VERSION 5.7 ;
  NOWIREEXTENSIONATPIN ON ;
  DIVIDERCHAR "/" ;
  BUSBITCHARS "[]" ;
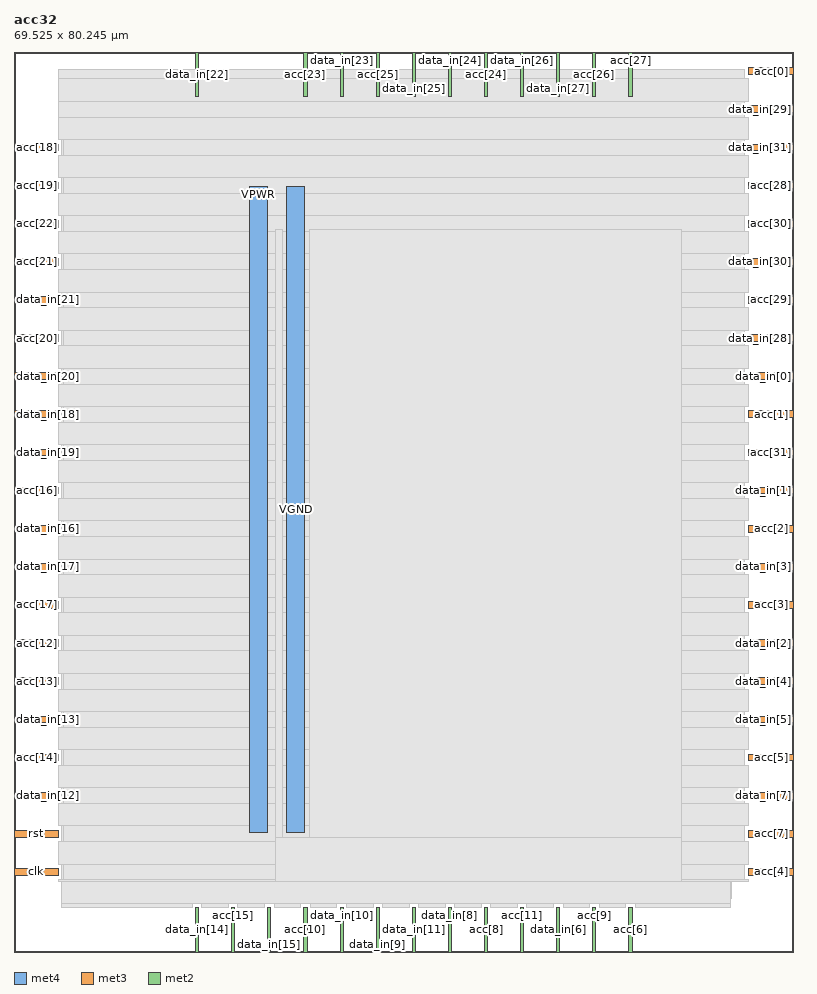
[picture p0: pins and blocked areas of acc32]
MACRO acc32
  CLASS BLOCK ;
  FOREIGN acc32 ;
  ORIGIN 0.000 0.000 ;
  SIZE 69.525 BY 80.245 ;
  PIN VGND
    DIRECTION INOUT ;
    USE GROUND ;
    PORT
      LAYER met4 ;
        RECT 24.340 10.640 25.940 68.240 ;
    END
  END VGND
  PIN VPWR
    DIRECTION INOUT ;
    USE POWER ;
    PORT
      LAYER met4 ;
        RECT 21.040 10.640 22.640 68.240 ;
    END
  END VPWR
  PIN acc[0]
    DIRECTION OUTPUT ;
    USE SIGNAL ;
    ANTENNADIFFAREA 0.445500 ;
    PORT
      LAYER met3 ;
        RECT 65.525 78.240 69.525 78.840 ;
    END
  END acc[0]
  PIN acc[10]
    DIRECTION OUTPUT ;
    USE SIGNAL ;
    ANTENNADIFFAREA 0.445500 ;
    PORT
      LAYER met2 ;
        RECT 25.850 0.000 26.130 4.000 ;
    END
  END acc[10]
  PIN acc[11]
    DIRECTION OUTPUT ;
    USE SIGNAL ;
    ANTENNADIFFAREA 0.445500 ;
    PORT
      LAYER met2 ;
        RECT 45.170 0.000 45.450 4.000 ;
    END
  END acc[11]
  PIN acc[12]
    DIRECTION OUTPUT ;
    USE SIGNAL ;
    ANTENNADIFFAREA 0.445500 ;
    PORT
      LAYER met3 ;
        RECT 0.000 27.240 4.000 27.840 ;
    END
  END acc[12]
  PIN acc[13]
    DIRECTION OUTPUT ;
    USE SIGNAL ;
    ANTENNADIFFAREA 0.445500 ;
    PORT
      LAYER met3 ;
        RECT 0.000 23.840 4.000 24.440 ;
    END
  END acc[13]
  PIN acc[14]
    DIRECTION OUTPUT ;
    USE SIGNAL ;
    ANTENNADIFFAREA 0.445500 ;
    PORT
      LAYER met3 ;
        RECT 0.000 17.040 4.000 17.640 ;
    END
  END acc[14]
  PIN acc[15]
    DIRECTION OUTPUT ;
    USE SIGNAL ;
    ANTENNADIFFAREA 0.445500 ;
    PORT
      LAYER met2 ;
        RECT 19.410 0.000 19.690 4.000 ;
    END
  END acc[15]
  PIN acc[16]
    DIRECTION OUTPUT ;
    USE SIGNAL ;
    ANTENNADIFFAREA 0.445500 ;
    PORT
      LAYER met3 ;
        RECT 0.000 40.840 4.000 41.440 ;
    END
  END acc[16]
  PIN acc[17]
    DIRECTION OUTPUT ;
    USE SIGNAL ;
    ANTENNADIFFAREA 0.445500 ;
    PORT
      LAYER met3 ;
        RECT 0.000 30.640 4.000 31.240 ;
    END
  END acc[17]
  PIN acc[18]
    DIRECTION OUTPUT ;
    USE SIGNAL ;
    ANTENNADIFFAREA 0.445500 ;
    PORT
      LAYER met3 ;
        RECT 0.000 71.440 4.000 72.040 ;
    END
  END acc[18]
  PIN acc[19]
    DIRECTION OUTPUT ;
    USE SIGNAL ;
    ANTENNADIFFAREA 0.445500 ;
    PORT
      LAYER met3 ;
        RECT 0.000 68.040 4.000 68.640 ;
    END
  END acc[19]
  PIN acc[1]
    DIRECTION OUTPUT ;
    USE SIGNAL ;
    ANTENNADIFFAREA 0.445500 ;
    PORT
      LAYER met3 ;
        RECT 65.525 47.640 69.525 48.240 ;
    END
  END acc[1]
  PIN acc[20]
    DIRECTION OUTPUT ;
    USE SIGNAL ;
    ANTENNADIFFAREA 0.445500 ;
    PORT
      LAYER met3 ;
        RECT 0.000 54.440 4.000 55.040 ;
    END
  END acc[20]
  PIN acc[21]
    DIRECTION OUTPUT ;
    USE SIGNAL ;
    ANTENNADIFFAREA 0.445500 ;
    PORT
      LAYER met3 ;
        RECT 0.000 61.240 4.000 61.840 ;
    END
  END acc[21]
  PIN acc[22]
    DIRECTION OUTPUT ;
    USE SIGNAL ;
    ANTENNADIFFAREA 0.445500 ;
    PORT
      LAYER met3 ;
        RECT 0.000 64.640 4.000 65.240 ;
    END
  END acc[22]
  PIN acc[23]
    DIRECTION OUTPUT ;
    USE SIGNAL ;
    ANTENNADIFFAREA 0.445500 ;
    PORT
      LAYER met2 ;
        RECT 25.850 76.245 26.130 80.245 ;
    END
  END acc[23]
  PIN acc[24]
    DIRECTION OUTPUT ;
    USE SIGNAL ;
    ANTENNADIFFAREA 0.445500 ;
    PORT
      LAYER met2 ;
        RECT 41.950 76.245 42.230 80.245 ;
    END
  END acc[24]
  PIN acc[25]
    DIRECTION OUTPUT ;
    USE SIGNAL ;
    ANTENNADIFFAREA 0.445500 ;
    PORT
      LAYER met2 ;
        RECT 32.290 76.245 32.570 80.245 ;
    END
  END acc[25]
  PIN acc[26]
    DIRECTION OUTPUT ;
    USE SIGNAL ;
    ANTENNADIFFAREA 0.445500 ;
    PORT
      LAYER met2 ;
        RECT 51.610 76.245 51.890 80.245 ;
    END
  END acc[26]
  PIN acc[27]
    DIRECTION OUTPUT ;
    USE SIGNAL ;
    ANTENNADIFFAREA 0.445500 ;
    PORT
      LAYER met2 ;
        RECT 54.830 76.245 55.110 80.245 ;
    END
  END acc[27]
  PIN acc[28]
    DIRECTION OUTPUT ;
    USE SIGNAL ;
    ANTENNADIFFAREA 0.445500 ;
    PORT
      LAYER met3 ;
        RECT 65.525 68.040 69.525 68.640 ;
    END
  END acc[28]
  PIN acc[29]
    DIRECTION OUTPUT ;
    USE SIGNAL ;
    ANTENNADIFFAREA 0.445500 ;
    PORT
      LAYER met3 ;
        RECT 65.525 57.840 69.525 58.440 ;
    END
  END acc[29]
  PIN acc[2]
    DIRECTION OUTPUT ;
    USE SIGNAL ;
    ANTENNADIFFAREA 0.445500 ;
    PORT
      LAYER met3 ;
        RECT 65.525 37.440 69.525 38.040 ;
    END
  END acc[2]
  PIN acc[30]
    DIRECTION OUTPUT ;
    USE SIGNAL ;
    ANTENNADIFFAREA 0.445500 ;
    PORT
      LAYER met3 ;
        RECT 65.525 64.640 69.525 65.240 ;
    END
  END acc[30]
  PIN acc[31]
    DIRECTION OUTPUT ;
    USE SIGNAL ;
    ANTENNADIFFAREA 0.445500 ;
    PORT
      LAYER met3 ;
        RECT 65.525 44.240 69.525 44.840 ;
    END
  END acc[31]
  PIN acc[3]
    DIRECTION OUTPUT ;
    USE SIGNAL ;
    ANTENNADIFFAREA 0.445500 ;
    PORT
      LAYER met3 ;
        RECT 65.525 30.640 69.525 31.240 ;
    END
  END acc[3]
  PIN acc[4]
    DIRECTION OUTPUT ;
    USE SIGNAL ;
    ANTENNADIFFAREA 0.445500 ;
    PORT
      LAYER met3 ;
        RECT 65.525 6.840 69.525 7.440 ;
    END
  END acc[4]
  PIN acc[5]
    DIRECTION OUTPUT ;
    USE SIGNAL ;
    ANTENNADIFFAREA 0.445500 ;
    PORT
      LAYER met3 ;
        RECT 65.525 17.040 69.525 17.640 ;
    END
  END acc[5]
  PIN acc[6]
    DIRECTION OUTPUT ;
    USE SIGNAL ;
    ANTENNADIFFAREA 0.445500 ;
    PORT
      LAYER met2 ;
        RECT 54.830 0.000 55.110 4.000 ;
    END
  END acc[6]
  PIN acc[7]
    DIRECTION OUTPUT ;
    USE SIGNAL ;
    ANTENNADIFFAREA 0.445500 ;
    PORT
      LAYER met3 ;
        RECT 65.525 10.240 69.525 10.840 ;
    END
  END acc[7]
  PIN acc[8]
    DIRECTION OUTPUT ;
    USE SIGNAL ;
    ANTENNADIFFAREA 0.445500 ;
    PORT
      LAYER met2 ;
        RECT 41.950 0.000 42.230 4.000 ;
    END
  END acc[8]
  PIN acc[9]
    DIRECTION OUTPUT ;
    USE SIGNAL ;
    ANTENNADIFFAREA 0.445500 ;
    PORT
      LAYER met2 ;
        RECT 51.610 0.000 51.890 4.000 ;
    END
  END acc[9]
  PIN clk
    DIRECTION INPUT ;
    USE SIGNAL ;
    ANTENNAGATEAREA 0.852000 ;
    PORT
      LAYER met3 ;
        RECT 0.000 6.840 4.000 7.440 ;
    END
  END clk
  PIN data_in[0]
    DIRECTION INPUT ;
    USE SIGNAL ;
    ANTENNAGATEAREA 0.196500 ;
    PORT
      LAYER met3 ;
        RECT 65.525 51.040 69.525 51.640 ;
    END
  END data_in[0]
  PIN data_in[10]
    DIRECTION INPUT ;
    USE SIGNAL ;
    ANTENNAGATEAREA 0.196500 ;
    PORT
      LAYER met2 ;
        RECT 29.070 0.000 29.350 4.000 ;
    END
  END data_in[10]
  PIN data_in[11]
    DIRECTION INPUT ;
    USE SIGNAL ;
    ANTENNAGATEAREA 0.196500 ;
    PORT
      LAYER met2 ;
        RECT 35.510 0.000 35.790 4.000 ;
    END
  END data_in[11]
  PIN data_in[12]
    DIRECTION INPUT ;
    USE SIGNAL ;
    ANTENNAGATEAREA 0.196500 ;
    PORT
      LAYER met3 ;
        RECT 0.000 13.640 4.000 14.240 ;
    END
  END data_in[12]
  PIN data_in[13]
    DIRECTION INPUT ;
    USE SIGNAL ;
    ANTENNAGATEAREA 0.196500 ;
    PORT
      LAYER met3 ;
        RECT 0.000 20.440 4.000 21.040 ;
    END
  END data_in[13]
  PIN data_in[14]
    DIRECTION INPUT ;
    USE SIGNAL ;
    ANTENNAGATEAREA 0.196500 ;
    PORT
      LAYER met2 ;
        RECT 16.190 0.000 16.470 4.000 ;
    END
  END data_in[14]
  PIN data_in[15]
    DIRECTION INPUT ;
    USE SIGNAL ;
    ANTENNAGATEAREA 0.196500 ;
    PORT
      LAYER met2 ;
        RECT 22.630 0.000 22.910 4.000 ;
    END
  END data_in[15]
  PIN data_in[16]
    DIRECTION INPUT ;
    USE SIGNAL ;
    ANTENNAGATEAREA 0.196500 ;
    PORT
      LAYER met3 ;
        RECT 0.000 37.440 4.000 38.040 ;
    END
  END data_in[16]
  PIN data_in[17]
    DIRECTION INPUT ;
    USE SIGNAL ;
    ANTENNAGATEAREA 0.196500 ;
    PORT
      LAYER met3 ;
        RECT 0.000 34.040 4.000 34.640 ;
    END
  END data_in[17]
  PIN data_in[18]
    DIRECTION INPUT ;
    USE SIGNAL ;
    ANTENNAGATEAREA 0.196500 ;
    PORT
      LAYER met3 ;
        RECT 0.000 47.640 4.000 48.240 ;
    END
  END data_in[18]
  PIN data_in[19]
    DIRECTION INPUT ;
    USE SIGNAL ;
    ANTENNAGATEAREA 0.196500 ;
    PORT
      LAYER met3 ;
        RECT 0.000 44.240 4.000 44.840 ;
    END
  END data_in[19]
  PIN data_in[1]
    DIRECTION INPUT ;
    USE SIGNAL ;
    ANTENNAGATEAREA 0.196500 ;
    PORT
      LAYER met3 ;
        RECT 65.525 40.840 69.525 41.440 ;
    END
  END data_in[1]
  PIN data_in[20]
    DIRECTION INPUT ;
    USE SIGNAL ;
    ANTENNAGATEAREA 0.196500 ;
    PORT
      LAYER met3 ;
        RECT 0.000 51.040 4.000 51.640 ;
    END
  END data_in[20]
  PIN data_in[21]
    DIRECTION INPUT ;
    USE SIGNAL ;
    ANTENNAGATEAREA 0.196500 ;
    PORT
      LAYER met3 ;
        RECT 0.000 57.840 4.000 58.440 ;
    END
  END data_in[21]
  PIN data_in[22]
    DIRECTION INPUT ;
    USE SIGNAL ;
    ANTENNAGATEAREA 0.196500 ;
    PORT
      LAYER met2 ;
        RECT 16.190 76.245 16.470 80.245 ;
    END
  END data_in[22]
  PIN data_in[23]
    DIRECTION INPUT ;
    USE SIGNAL ;
    ANTENNAGATEAREA 0.196500 ;
    PORT
      LAYER met2 ;
        RECT 29.070 76.245 29.350 80.245 ;
    END
  END data_in[23]
  PIN data_in[24]
    DIRECTION INPUT ;
    USE SIGNAL ;
    ANTENNAGATEAREA 0.196500 ;
    PORT
      LAYER met2 ;
        RECT 38.730 76.245 39.010 80.245 ;
    END
  END data_in[24]
  PIN data_in[25]
    DIRECTION INPUT ;
    USE SIGNAL ;
    ANTENNAGATEAREA 0.196500 ;
    PORT
      LAYER met2 ;
        RECT 35.510 76.245 35.790 80.245 ;
    END
  END data_in[25]
  PIN data_in[26]
    DIRECTION INPUT ;
    USE SIGNAL ;
    ANTENNAGATEAREA 0.196500 ;
    PORT
      LAYER met2 ;
        RECT 45.170 76.245 45.450 80.245 ;
    END
  END data_in[26]
  PIN data_in[27]
    DIRECTION INPUT ;
    USE SIGNAL ;
    ANTENNAGATEAREA 0.196500 ;
    PORT
      LAYER met2 ;
        RECT 48.390 76.245 48.670 80.245 ;
    END
  END data_in[27]
  PIN data_in[28]
    DIRECTION INPUT ;
    USE SIGNAL ;
    ANTENNAGATEAREA 0.196500 ;
    PORT
      LAYER met3 ;
        RECT 65.525 54.440 69.525 55.040 ;
    END
  END data_in[28]
  PIN data_in[29]
    DIRECTION INPUT ;
    USE SIGNAL ;
    ANTENNAGATEAREA 0.196500 ;
    PORT
      LAYER met3 ;
        RECT 65.525 74.840 69.525 75.440 ;
    END
  END data_in[29]
  PIN data_in[2]
    DIRECTION INPUT ;
    USE SIGNAL ;
    ANTENNAGATEAREA 0.196500 ;
    PORT
      LAYER met3 ;
        RECT 65.525 27.240 69.525 27.840 ;
    END
  END data_in[2]
  PIN data_in[30]
    DIRECTION INPUT ;
    USE SIGNAL ;
    ANTENNAGATEAREA 0.196500 ;
    PORT
      LAYER met3 ;
        RECT 65.525 61.240 69.525 61.840 ;
    END
  END data_in[30]
  PIN data_in[31]
    DIRECTION INPUT ;
    USE SIGNAL ;
    ANTENNAGATEAREA 0.196500 ;
    PORT
      LAYER met3 ;
        RECT 65.525 71.440 69.525 72.040 ;
    END
  END data_in[31]
  PIN data_in[3]
    DIRECTION INPUT ;
    USE SIGNAL ;
    ANTENNAGATEAREA 0.213000 ;
    PORT
      LAYER met3 ;
        RECT 65.525 34.040 69.525 34.640 ;
    END
  END data_in[3]
  PIN data_in[4]
    DIRECTION INPUT ;
    USE SIGNAL ;
    ANTENNAGATEAREA 0.196500 ;
    PORT
      LAYER met3 ;
        RECT 65.525 23.840 69.525 24.440 ;
    END
  END data_in[4]
  PIN data_in[5]
    DIRECTION INPUT ;
    USE SIGNAL ;
    ANTENNAGATEAREA 0.196500 ;
    PORT
      LAYER met3 ;
        RECT 65.525 20.440 69.525 21.040 ;
    END
  END data_in[5]
  PIN data_in[6]
    DIRECTION INPUT ;
    USE SIGNAL ;
    ANTENNAGATEAREA 0.196500 ;
    PORT
      LAYER met2 ;
        RECT 48.390 0.000 48.670 4.000 ;
    END
  END data_in[6]
  PIN data_in[7]
    DIRECTION INPUT ;
    USE SIGNAL ;
    ANTENNAGATEAREA 0.196500 ;
    PORT
      LAYER met3 ;
        RECT 65.525 13.640 69.525 14.240 ;
    END
  END data_in[7]
  PIN data_in[8]
    DIRECTION INPUT ;
    USE SIGNAL ;
    ANTENNAGATEAREA 0.196500 ;
    PORT
      LAYER met2 ;
        RECT 38.730 0.000 39.010 4.000 ;
    END
  END data_in[8]
  PIN data_in[9]
    DIRECTION INPUT ;
    USE SIGNAL ;
    ANTENNAGATEAREA 0.196500 ;
    PORT
      LAYER met2 ;
        RECT 32.290 0.000 32.570 4.000 ;
    END
  END data_in[9]
  PIN rst
    DIRECTION INPUT ;
    USE SIGNAL ;
    ANTENNAGATEAREA 0.126000 ;
    PORT
      LAYER met3 ;
        RECT 0.000 10.240 4.000 10.840 ;
    END
  END rst
  OBS
      LAYER nwell ;
        RECT 5.330 10.795 64.130 68.190 ;
      LAYER li1 ;
        RECT 5.520 10.795 63.940 68.085 ;
      LAYER met1 ;
        RECT 4.210 4.800 63.940 69.320 ;
      LAYER met2 ;
        RECT 4.230 75.965 15.910 78.725 ;
        RECT 16.750 75.965 25.570 78.725 ;
        RECT 26.410 75.965 28.790 78.725 ;
        RECT 29.630 75.965 32.010 78.725 ;
        RECT 32.850 75.965 35.230 78.725 ;
        RECT 36.070 75.965 38.450 78.725 ;
        RECT 39.290 75.965 41.670 78.725 ;
        RECT 42.510 75.965 44.890 78.725 ;
        RECT 45.730 75.965 48.110 78.725 ;
        RECT 48.950 75.965 51.330 78.725 ;
        RECT 52.170 75.965 54.550 78.725 ;
        RECT 55.390 75.965 63.850 78.725 ;
        RECT 4.230 4.280 63.850 75.965 ;
        RECT 4.230 4.000 15.910 4.280 ;
        RECT 16.750 4.000 19.130 4.280 ;
        RECT 19.970 4.000 22.350 4.280 ;
        RECT 23.190 4.000 25.570 4.280 ;
        RECT 26.410 4.000 28.790 4.280 ;
        RECT 29.630 4.000 32.010 4.280 ;
        RECT 32.850 4.000 35.230 4.280 ;
        RECT 36.070 4.000 38.450 4.280 ;
        RECT 39.290 4.000 41.670 4.280 ;
        RECT 42.510 4.000 44.890 4.280 ;
        RECT 45.730 4.000 48.110 4.280 ;
        RECT 48.950 4.000 51.330 4.280 ;
        RECT 52.170 4.000 54.550 4.280 ;
        RECT 55.390 4.000 63.850 4.280 ;
      LAYER met3 ;
        RECT 3.990 77.840 65.125 78.705 ;
        RECT 3.990 75.840 65.525 77.840 ;
        RECT 3.990 74.440 65.125 75.840 ;
        RECT 3.990 72.440 65.525 74.440 ;
        RECT 4.400 71.040 65.125 72.440 ;
        RECT 3.990 69.040 65.525 71.040 ;
        RECT 4.400 67.640 65.125 69.040 ;
        RECT 3.990 65.640 65.525 67.640 ;
        RECT 4.400 64.240 65.125 65.640 ;
        RECT 3.990 62.240 65.525 64.240 ;
        RECT 4.400 60.840 65.125 62.240 ;
        RECT 3.990 58.840 65.525 60.840 ;
        RECT 4.400 57.440 65.125 58.840 ;
        RECT 3.990 55.440 65.525 57.440 ;
        RECT 4.400 54.040 65.125 55.440 ;
        RECT 3.990 52.040 65.525 54.040 ;
        RECT 4.400 50.640 65.125 52.040 ;
        RECT 3.990 48.640 65.525 50.640 ;
        RECT 4.400 47.240 65.125 48.640 ;
        RECT 3.990 45.240 65.525 47.240 ;
        RECT 4.400 43.840 65.125 45.240 ;
        RECT 3.990 41.840 65.525 43.840 ;
        RECT 4.400 40.440 65.125 41.840 ;
        RECT 3.990 38.440 65.525 40.440 ;
        RECT 4.400 37.040 65.125 38.440 ;
        RECT 3.990 35.040 65.525 37.040 ;
        RECT 4.400 33.640 65.125 35.040 ;
        RECT 3.990 31.640 65.525 33.640 ;
        RECT 4.400 30.240 65.125 31.640 ;
        RECT 3.990 28.240 65.525 30.240 ;
        RECT 4.400 26.840 65.125 28.240 ;
        RECT 3.990 24.840 65.525 26.840 ;
        RECT 4.400 23.440 65.125 24.840 ;
        RECT 3.990 21.440 65.525 23.440 ;
        RECT 4.400 20.040 65.125 21.440 ;
        RECT 3.990 18.040 65.525 20.040 ;
        RECT 4.400 16.640 65.125 18.040 ;
        RECT 3.990 14.640 65.525 16.640 ;
        RECT 4.400 13.240 65.125 14.640 ;
        RECT 3.990 11.240 65.525 13.240 ;
        RECT 4.400 9.840 65.125 11.240 ;
        RECT 3.990 7.840 65.525 9.840 ;
        RECT 4.400 6.440 65.125 7.840 ;
        RECT 3.990 6.295 65.525 6.440 ;
      LAYER met4 ;
        RECT 23.295 10.240 23.940 64.425 ;
        RECT 26.340 10.240 59.505 64.425 ;
        RECT 23.295 6.295 59.505 10.240 ;
  END
END acc32
END LIBRARY

